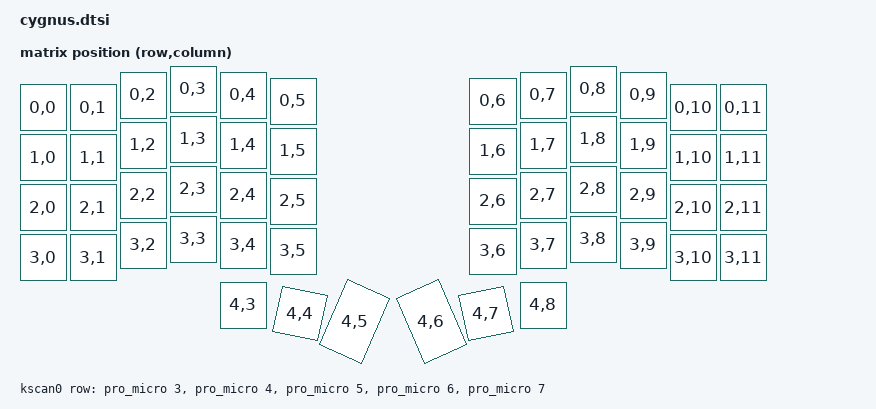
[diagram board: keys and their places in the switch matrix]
#include <dt-bindings/zmk/matrix_transform.h>

/ {
    chosen {
        zmk,physical-layout = &default_layout;
        zmk,studio-rpc-uart = &uart1;
    };

    // New node to fix the "undefined node label 'key_physical_attrs'" error
    key_physical_attrs: key_physical_attrs {
        compatible = "zmk,key-physical-attrs";
				#key-cells = <7>;
    };

    default_transform: default_transform {
        compatible = "zmk,matrix-transform";
        columns = <12>;
        rows = <5>;
// | SW1  | SW2  | SW3  | SW4  | SW5  | SW6  |                 | SW6  | SW5  | SW4  | SW3  | SW2  | SW1  |
// | SW7  | SW8  | SW9  | SW10 | SW11 | SW12 |                 | SW12 | SW11 | SW10 | SW9  | SW8  | SW7  |
// | SW13 | SW14 | SW15 | SW16 | SW17 | SW18 |                 | SW18 | SW17 | SW16 | SW15 | SW14 | SW13 |
// | SW19 | SW20 | SW21 | SW22 | SW23 | SW24 |                 | SW24 | SW23 | SW22 | SW21 | SW20 | SW19 |
//                             | SW25 | SW26 | SW27 |   | SW27 | SW26 | SW25 |
        map = <
RC(0,0) RC(0,1) RC(0,2) RC(0,3) RC(0,4) RC(0,5)    RC(0,6) RC(0,7) RC(0,8) RC(0,9) RC(0,10) RC(0,11)
RC(1,0) RC(1,1) RC(1,2) RC(1,3) RC(1,4) RC(1,5)    RC(1,6) RC(1,7) RC(1,8) RC(1,9) RC(1,10) RC(1,11)
RC(2,0) RC(2,1) RC(2,2) RC(2,3) RC(2,4) RC(2,5)    RC(2,6) RC(2,7) RC(2,8) RC(2,9) RC(2,10) RC(2,11)
RC(3,0) RC(3,1) RC(3,2) RC(3,3) RC(3,4) RC(3,5)    RC(3,6) RC(3,7) RC(3,8) RC(3,9) RC(3,10) RC(3,11)
                        RC(4,3) RC(4,4) RC(4,5)    RC(4,6) RC(4,7) RC(4,8)
        >;
    };

    kscan0: kscan {
        compatible = "zmk,kscan-gpio-matrix";

        diode-direction = "col2row";
        row-gpios 
            = <&pro_micro 3 (GPIO_ACTIVE_HIGH | GPIO_PULL_DOWN)>
            , <&pro_micro 4 (GPIO_ACTIVE_HIGH | GPIO_PULL_DOWN)>
            , <&pro_micro 5 (GPIO_ACTIVE_HIGH | GPIO_PULL_DOWN)>
            , <&pro_micro 6 (GPIO_ACTIVE_HIGH | GPIO_PULL_DOWN)>
            , <&pro_micro 7 (GPIO_ACTIVE_HIGH | GPIO_PULL_DOWN)>
            ;
    };

    default_layout: default_layout {
        compatible = "zmk,physical-layout";
        display-name = "Default";
        
        transform = <&default_transform>;
        kscan = <&kscan0>;
        
        // Corrected the DTS syntax: used '=' only once, then ',' for continuation.
        keys
#include <physical_layouts.dtsi>

/ {
    physical_layout0: physical_layout_0 {
        compatible = "zmk,physical-layout";
        display-name = "Default";

        kscan = <&kscan0>;
        transform = <&matrix_transform0>;

        keys  //                     w   h    x    y     rot    rx    ry
            = <&key_physical_attrs 100 100    0   37       0     0     0>
            , <&key_physical_attrs 100 100  100   37       0     0     0>
            , <&key_physical_attrs 100 100  200   12       0     0     0>
            , <&key_physical_attrs 100 100  300    0       0     0     0>
            , <&key_physical_attrs 100 100  400   12       0     0     0>
            , <&key_physical_attrs 100 100  500   24       0     0     0>
            , <&key_physical_attrs 100 100  900   24       0     0     0>
            , <&key_physical_attrs 100 100 1000   12       0     0     0>
            , <&key_physical_attrs 100 100 1100    0       0     0     0>
            , <&key_physical_attrs 100 100 1200   12       0     0     0>
            , <&key_physical_attrs 100 100 1300   37       0     0     0>
            , <&key_physical_attrs 100 100 1400   37       0     0     0>
            , <&key_physical_attrs 100 100    0  137       0     0     0>
            , <&key_physical_attrs 100 100  100  137       0     0     0>
            , <&key_physical_attrs 100 100  200  112       0     0     0>
            , <&key_physical_attrs 100 100  300  100       0     0     0>
            , <&key_physical_attrs 100 100  400  112       0     0     0>
            , <&key_physical_attrs 100 100  500  124       0     0     0>
            , <&key_physical_attrs 100 100  900  124       0     0     0>
            , <&key_physical_attrs 100 100 1000  112       0     0     0>
            , <&key_physical_attrs 100 100 1100  100       0     0     0>
            , <&key_physical_attrs 100 100 1200  112       0     0     0>
            , <&key_physical_attrs 100 100 1300  137       0     0     0>
            , <&key_physical_attrs 100 100 1400  137       0     0     0>
            , <&key_physical_attrs 100 100    0  237       0     0     0>
            , <&key_physical_attrs 100 100  100  237       0     0     0>
            , <&key_physical_attrs 100 100  200  212       0     0     0>
            , <&key_physical_attrs 100 100  300  200       0     0     0>
            , <&key_physical_attrs 100 100  400  212       0     0     0>
            , <&key_physical_attrs 100 100  500  224       0     0     0>
            , <&key_physical_attrs 100 100  900  224       0     0     0>
            , <&key_physical_attrs 100 100 1000  212       0     0     0>
            , <&key_physical_attrs 100 100 1100  200       0     0     0>
            , <&key_physical_attrs 100 100 1200  212       0     0     0>
            , <&key_physical_attrs 100 100 1300  237       0     0     0>
            , <&key_physical_attrs 100 100 1400  237       0     0     0>
            , <&key_physical_attrs 100 100    0  337       0     0     0>
            , <&key_physical_attrs 100 100  100  337       0     0     0>
            , <&key_physical_attrs 100 100  200  312       0     0     0>
            , <&key_physical_attrs 100 100  300  300       0     0     0>
            , <&key_physical_attrs 100 100  400  312       0     0     0>
            , <&key_physical_attrs 100 100  500  324       0     0     0>
            , <&key_physical_attrs 100 100  900  324       0     0     0>
            , <&key_physical_attrs 100 100 1000  312       0     0     0>
            , <&key_physical_attrs 100 100 1100  300       0     0     0>
            , <&key_physical_attrs 100 100 1200  312       0     0     0>
            , <&key_physical_attrs 100 100 1300  337       0     0     0>
            , <&key_physical_attrs 100 100 1400  337       0     0     0>
            , <&key_physical_attrs 100 100  400  432       0     0     0>
            , <&key_physical_attrs 100 100  530  432    1200   490   412>
            , <&key_physical_attrs 100 150  650  403    2400   600   433>
            , <&key_physical_attrs 100 150  750  403 (-2400)   900   433>
            , <&key_physical_attrs 100 100  870  432 (-1200)  1010   412>
            , <&key_physical_attrs 100 100 1000  432       0     0     0>
            ;
    };
};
